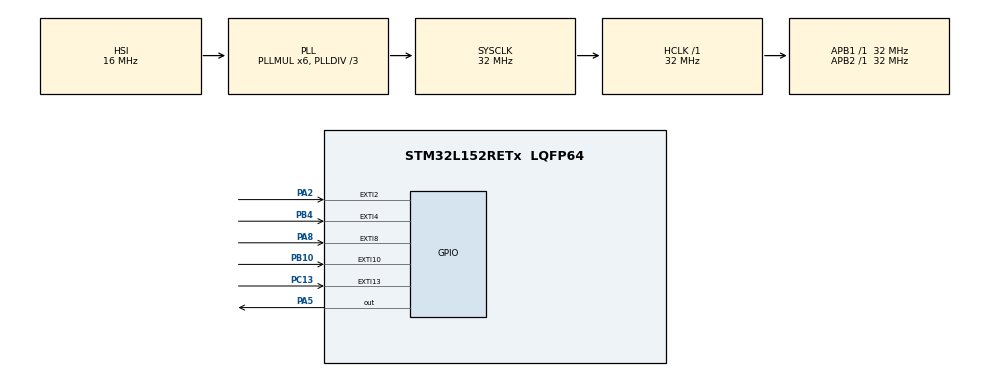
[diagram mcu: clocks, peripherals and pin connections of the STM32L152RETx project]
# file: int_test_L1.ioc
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Mcu.Family=STM32L1
Mcu.Name=STM32L152RETx
Mcu.Package=LQFP64
NVIC.EXTI15_10_IRQn=true\:0\:0\:false\:false\:true\:true
NVIC.EXTI2_IRQn=true\:0\:0\:false\:false\:true\:true
NVIC.EXTI4_IRQn=true\:0\:0\:false\:false\:true\:true
NVIC.EXTI9_5_IRQn=true\:0\:0\:false\:false\:true\:true
NVIC.PriorityGroup=NVIC_PRIORITYGROUP_0
PA2.Signal=GPXTI2
PA5.Signal=GPIO_Output
PA8.Signal=GPXTI8
PB10.Signal=GPXTI10
PB4.Signal=GPXTI4
PC13-WKUP2.GPIO_ModeDefaultEXTI=GPIO_MODE_IT_FALLING
PC13-WKUP2.Signal=GPXTI13
ProjectManager.HeapSize=0x200
ProjectManager.StackSize=0x400
ProjectManager.TargetToolchain=MDK-ARM V5
RCC.48MHZClocksFreq_Value=48000000
RCC.AHBFreq_Value=32000000
RCC.APB1Freq_Value=32000000
RCC.APB1TimFreq_Value=32000000
RCC.APB2Freq_Value=32000000
RCC.APB2TimFreq_Value=32000000
RCC.HCLKFreq_Value=32000000
RCC.HSE_VALUE=8000000
RCC.HSI_VALUE=16000000
RCC.MSI_VALUE=2097000
RCC.PLLDIV=RCC_PLL_DIV3
RCC.PLLMUL=RCC_PLL_MUL6
RCC.RTCClockSelectionVirtual=RCC_RTCCLKSOURCE_LSE
RCC.SYSCLKFreq_VALUE=32000000
RCC.SYSCLKSource=RCC_SYSCLKSOURCE_PLLCLK
RCC.USBOutput=48000000
RCC.VCOOutputFreq_Value=96000000
board=NUCLEO-L152RE

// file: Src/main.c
/* USER CODE BEGIN Header */
/**
  ******************************************************************************
  * @file           : main.c
  * @brief          : Main program body
  ******************************************************************************
  ** This notice applies to any and all portions of this file
  * that are not between comment pairs USER CODE BEGIN and
  * USER CODE END. Other portions of this file, whether
  * inserted by the user or by software development tools
  * are owned by their respective copyright owners.
  *
  * COPYRIGHT(c) 2019 STMicroelectronics
  *
  * Redistribution and use in source and binary forms, with or without modification,
  * are permitted provided that the following conditions are met:
  *   1. Redistributions of source code must retain the above copyright notice,
  *      this list of conditions and the following disclaimer.
  *   2. Redistributions in binary form must reproduce the above copyright notice,
  *      this list of conditions and the following disclaimer in the documentation
  *      and/or other materials provided with the distribution.
  *   3. Neither the name of STMicroelectronics nor the names of its contributors
  *      may be used to endorse or promote products derived from this software
  *      without specific prior written permission.
  *
  * THIS SOFTWARE IS PROVIDED BY THE COPYRIGHT HOLDERS AND CONTRIBUTORS "AS IS"
  * AND ANY EXPRESS OR IMPLIED WARRANTIES, INCLUDING, BUT NOT LIMITED TO, THE
  * IMPLIED WARRANTIES OF MERCHANTABILITY AND FITNESS FOR A PARTICULAR PURPOSE ARE
  * DISCLAIMED. IN NO EVENT SHALL THE COPYRIGHT HOLDER OR CONTRIBUTORS BE LIABLE
  * FOR ANY DIRECT, INDIRECT, INCIDENTAL, SPECIAL, EXEMPLARY, OR CONSEQUENTIAL
  * DAMAGES (INCLUDING, BUT NOT LIMITED TO, PROCUREMENT OF SUBSTITUTE GOODS OR
  * SERVICES; LOSS OF USE, DATA, OR PROFITS; OR BUSINESS INTERRUPTION) HOWEVER
  * CAUSED AND ON ANY THEORY OF LIABILITY, WHETHER IN CONTRACT, STRICT LIABILITY,
  * OR TORT (INCLUDING NEGLIGENCE OR OTHERWISE) ARISING IN ANY WAY OUT OF THE USE
  * OF THIS SOFTWARE, EVEN IF ADVISED OF THE POSSIBILITY OF SUCH DAMAGE.
  *
  ******************************************************************************
  */
/* USER CODE END Header */

#include "main.h"

/* USER CODE BEGIN Includes */
#include "PowerModes.h"
/* USER CODE END Includes */

/* USER CODE BEGIN PD */
#define DEBUG (0)
/* USER CODE END PD */

/* USER CODE BEGIN PV */
uint8_t globalIntterupt = 0;
States globalState = Detumble;
/* USER CODE END PV */

void SystemClock_Config(void);
static void MX_GPIO_Init(void);

int main(void)
{

  /* MCU Configuration--------------------------------------------------------*/

  /* Reset of all peripherals, Initializes the Flash interface and the Systick. */
  HAL_Init();

  /* Configure the system clock */
  SystemClock_Config();

  /* Initialize all configured peripherals */
  MX_GPIO_Init();
  /* USER CODE BEGIN 2 */

	/* Initialize Variables */
	States state;
	system_function functions;

	/* Initialize the starting state of each of the systems that need power */
	Initialize_Functions(&functions);

	/* Set Initial state */
	state = Detumble;
  /* USER CODE END 2 */

  /* Infinite loop */
  /* USER CODE BEGIN WHILE */
  while (1)
  {
	/* Enter the state machine */
		while(1)
		{
			globalState = state;
			switch (state)
			{
				/* In Detumble mode */
				case (Detumble):
					//if (DEBUG) printf("\nEntering Detumble mode\n");
					Set_PowerModes(&functions, Detumble);
					//Print_System_Settings(&functions);	// Used for testing and debugging
					// Set the pins high for each rail that should be one here //
					state = Transition(Detumble);
					break;
				/* In Kill mode */
				case (Kill):
					//if (DEBUG) printf("\nEntering Kill mode\n");
					Set_PowerModes(&functions, Kill);
					//Print_System_Settings(&functions);	// Used for testing and debugging
					// Set the pins high for each rail that should be one here //
					state = Transition(Kill);
					break;
				/* In Normal mode */
				case (Normal):
					//if (DEBUG) printf("\nEntering Normal mode\n");
					Set_PowerModes(&functions, Normal);
					//Print_System_Settings(&functions);	// Used for testing and debugging
					// Set the pins high for each rail that should be one here //
					state = Transition(Normal);
					break;
				/* In UltraLowPower mode */
				case (UltraLowPower):
					//if (DEBUG) printf("\nEntering UltraLowPower mode\n");
					Set_PowerModes(&functions, UltraLowPower);
					//Print_System_Settings(&functions);	// Used for testing and debugging
					// Set the pins high for each rail that should be one here //
					state = Transition(UltraLowPower);
					break;
				/* In LowPower mode */
				case (LowPower):
					//if (DEBUG) printf("\nEntering LowPower mode\n");
					Set_PowerModes(&functions, LowPower);
					//Print_System_Settings(&functions);	// Used for testing and debugging
					// Set the pins high for each rail that should be one here //
					state = Transition(LowPower);
					break;
				/* In Eclipse mode */
				case (Eclipse):
					//if (DEBUG) printf("\nEntering Eclipse mode\n");
					Set_PowerModes(&functions, Eclipse);
					//Print_System_Settings(&functions);	// Used for testing and debugging
					// Set the pins high for each rail that should be one here //
					state = Transition(Eclipse);
					break;
				/* In ScienceOnly mode */
				case (ScienceOnly):
					//if (DEBUG) printf("\nEntering ScienceOnly mode\n");
					Set_PowerModes(&functions, ScienceOnly);
					//Print_System_Settings(&functions);	// Used for testing and debugging
					// Set the pins high for each rail that should be one here //
					state = Transition(ScienceOnly);
					break;
				/* An error occurred */
				default:
					state = 255; // Error
					//fprintf(stderr, "\nInvalid state in the state machine reached...\nExiting\n");
					continue;
			}
		}

    /* USER CODE END WHILE */

  }
}

void SystemClock_Config(void)
{
  RCC_OscInitTypeDef RCC_OscInitStruct = {0};
  RCC_ClkInitTypeDef RCC_ClkInitStruct = {0};

  /**Configure the main internal regulator output voltage
  */
  __HAL_PWR_VOLTAGESCALING_CONFIG(PWR_REGULATOR_VOLTAGE_SCALE1);
  /**Initializes the CPU, AHB and APB busses clocks
  */
  RCC_OscInitStruct.OscillatorType = RCC_OSCILLATORTYPE_HSI;
  RCC_OscInitStruct.HSIState = RCC_HSI_ON;
  RCC_OscInitStruct.HSICalibrationValue = RCC_HSICALIBRATION_DEFAULT;
  RCC_OscInitStruct.PLL.PLLState = RCC_PLL_ON;
  RCC_OscInitStruct.PLL.PLLSource = RCC_PLLSOURCE_HSI;
  RCC_OscInitStruct.PLL.PLLMUL = RCC_PLL_MUL6;
  RCC_OscInitStruct.PLL.PLLDIV = RCC_PLL_DIV3;
  if (HAL_RCC_OscConfig(&RCC_OscInitStruct) != HAL_OK)
  {
    Error_Handler();
  }
  /**Initializes the CPU, AHB and APB busses clocks
  */
  RCC_ClkInitStruct.ClockType = RCC_CLOCKTYPE_HCLK|RCC_CLOCKTYPE_SYSCLK
                              |RCC_CLOCKTYPE_PCLK1|RCC_CLOCKTYPE_PCLK2;
  RCC_ClkInitStruct.SYSCLKSource = RCC_SYSCLKSOURCE_PLLCLK;
  RCC_ClkInitStruct.AHBCLKDivider = RCC_SYSCLK_DIV1;
  RCC_ClkInitStruct.APB1CLKDivider = RCC_HCLK_DIV1;
  RCC_ClkInitStruct.APB2CLKDivider = RCC_HCLK_DIV1;

  if (HAL_RCC_ClockConfig(&RCC_ClkInitStruct, FLASH_LATENCY_1) != HAL_OK)
  {
    Error_Handler();
  }
}

static void MX_GPIO_Init(void)
{
  GPIO_InitTypeDef GPIO_InitStruct = {0};

  /* GPIO Ports Clock Enable */
  __HAL_RCC_GPIOC_CLK_ENABLE();
  __HAL_RCC_GPIOA_CLK_ENABLE();
  __HAL_RCC_GPIOB_CLK_ENABLE();

  /*Configure GPIO pin Output Level */
  HAL_GPIO_WritePin(GPIOA, GPIO_PIN_5|ULOW_PIN_Pin|LOW_PIN_Pin|DETUMBLE_PIN_Pin, GPIO_PIN_RESET);

  /*Configure GPIO pin Output Level */
  HAL_GPIO_WritePin(GPIOC, GPIO_PIN_6|ECLIPSE_PIN_Pin, GPIO_PIN_RESET);

  /*Configure GPIO pin Output Level */
  HAL_GPIO_WritePin(GPIOB, NORMAL_PIN_Pin|DEAD_PIN_Pin|SCILOG_PIN_Pin, GPIO_PIN_RESET);

  /*Configure GPIO pin : PC13 */
  GPIO_InitStruct.Pin = GPIO_PIN_13;
  GPIO_InitStruct.Mode = GPIO_MODE_IT_FALLING;
  GPIO_InitStruct.Pull = GPIO_NOPULL;
  HAL_GPIO_Init(GPIOC, &GPIO_InitStruct);

  /*Configure GPIO pins : PA2 PA8 */
  GPIO_InitStruct.Pin = GPIO_PIN_2|GPIO_PIN_8;
  GPIO_InitStruct.Mode = GPIO_MODE_IT_RISING;
  GPIO_InitStruct.Pull = GPIO_NOPULL;
  HAL_GPIO_Init(GPIOA, &GPIO_InitStruct);

  /*Configure GPIO pins : PA5 ULOW_PIN_Pin LOW_PIN_Pin DETUMBLE_PIN_Pin */
  GPIO_InitStruct.Pin = GPIO_PIN_5|ULOW_PIN_Pin|LOW_PIN_Pin|DETUMBLE_PIN_Pin;
  GPIO_InitStruct.Mode = GPIO_MODE_OUTPUT_PP;
  GPIO_InitStruct.Pull = GPIO_NOPULL;
  GPIO_InitStruct.Speed = GPIO_SPEED_FREQ_LOW;
  HAL_GPIO_Init(GPIOA, &GPIO_InitStruct);

  /*Configure GPIO pins : PB10 PB4 */
  GPIO_InitStruct.Pin = GPIO_PIN_10|GPIO_PIN_4;
  GPIO_InitStruct.Mode = GPIO_MODE_IT_RISING;
  GPIO_InitStruct.Pull = GPIO_NOPULL;
  HAL_GPIO_Init(GPIOB, &GPIO_InitStruct);

  /*Configure GPIO pins : PC6 ECLIPSE_PIN_Pin */
  GPIO_InitStruct.Pin = GPIO_PIN_6|ECLIPSE_PIN_Pin;
  GPIO_InitStruct.Mode = GPIO_MODE_OUTPUT_PP;
  GPIO_InitStruct.Pull = GPIO_NOPULL;
  GPIO_InitStruct.Speed = GPIO_SPEED_FREQ_LOW;
  HAL_GPIO_Init(GPIOC, &GPIO_InitStruct);

  /*Configure GPIO pins : NORMAL_PIN_Pin DEAD_PIN_Pin SCILOG_PIN_Pin */
  GPIO_InitStruct.Pin = NORMAL_PIN_Pin|DEAD_PIN_Pin|SCILOG_PIN_Pin;
  GPIO_InitStruct.Mode = GPIO_MODE_OUTPUT_PP;
  GPIO_InitStruct.Pull = GPIO_NOPULL;
  GPIO_InitStruct.Speed = GPIO_SPEED_FREQ_LOW;
  HAL_GPIO_Init(GPIOB, &GPIO_InitStruct);

  /* EXTI interrupt init*/
  HAL_NVIC_SetPriority(EXTI2_IRQn, 0, 0);
  HAL_NVIC_EnableIRQ(EXTI2_IRQn);

  HAL_NVIC_SetPriority(EXTI4_IRQn, 0, 0);
  HAL_NVIC_EnableIRQ(EXTI4_IRQn);

  HAL_NVIC_SetPriority(EXTI9_5_IRQn, 0, 0);
  HAL_NVIC_EnableIRQ(EXTI9_5_IRQn);

  HAL_NVIC_SetPriority(EXTI15_10_IRQn, 0, 0);
  HAL_NVIC_EnableIRQ(EXTI15_10_IRQn);

}

/* USER CODE BEGIN 4 */

void HAL_GPIO_EXTI_Callback(uint16_t GPIO_PIN)
	{
		if (GPIO_PIN == GPIO_PIN_13)
		{
			change_variables(STABLE);
			globalIntterupt = 13;
			HAL_GPIO_TogglePin(GPIOA , GPIO_PIN_5);
		}
		else if (GPIO_PIN == GPIO_PIN_8)
		{
			change_variables(SCI_EVENT);
			globalIntterupt = 8;
			HAL_GPIO_TogglePin(GPIOA , GPIO_PIN_5);
		}
		/*else if (GPIO_PIN == GPIO_PIN_10)
		{
			change_variables(DIE);
			globalIntterupt = 3;
			HAL_GPIO_TogglePin(GPIOA , GPIO_PIN_5);
		} */
		else if (GPIO_PIN == GPIO_PIN_2)
		{
			change_variables(BATT);
			globalIntterupt = 2;
			HAL_GPIO_TogglePin(GPIOA , GPIO_PIN_5);
		}
		else if (GPIO_PIN == GPIO_PIN_4)
		{
			change_variables(SOLAR);
			globalIntterupt = 4;
			HAL_GPIO_TogglePin(GPIOA , GPIO_PIN_5);
		}
		else
		{
			__NOP();
		}
	}

/* USER CODE END 4 */

void Error_Handler(void)
{
}

/************************ (C) COPYRIGHT STMicroelectronics *****END OF FILE****/
